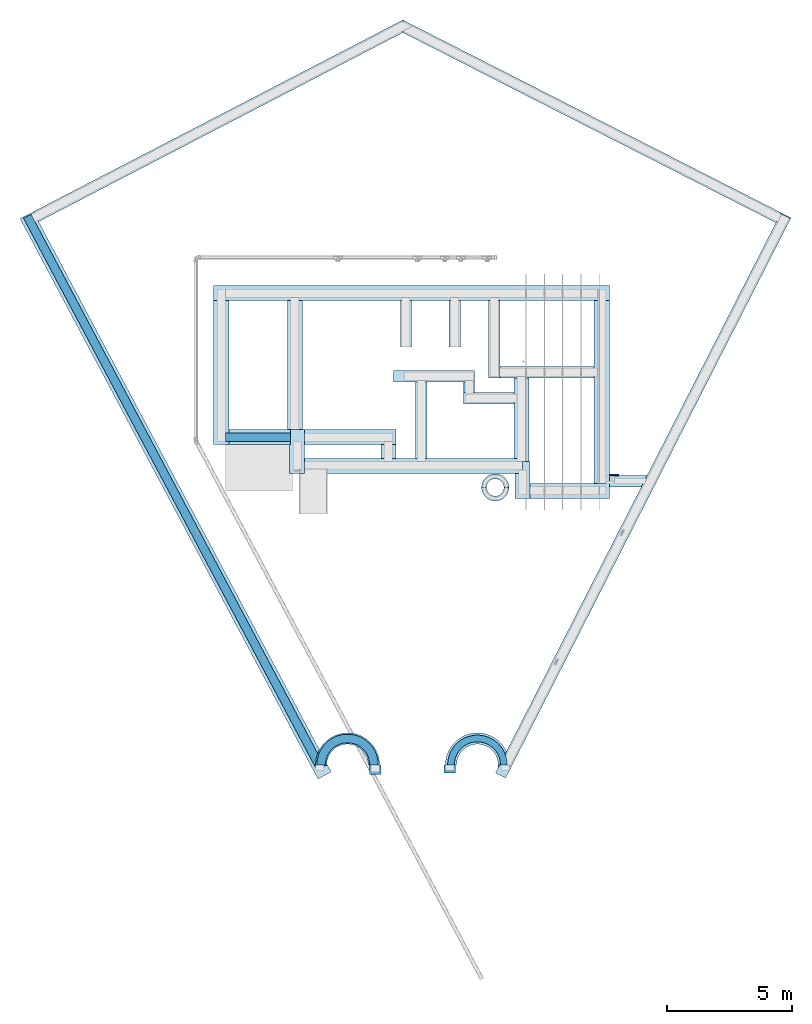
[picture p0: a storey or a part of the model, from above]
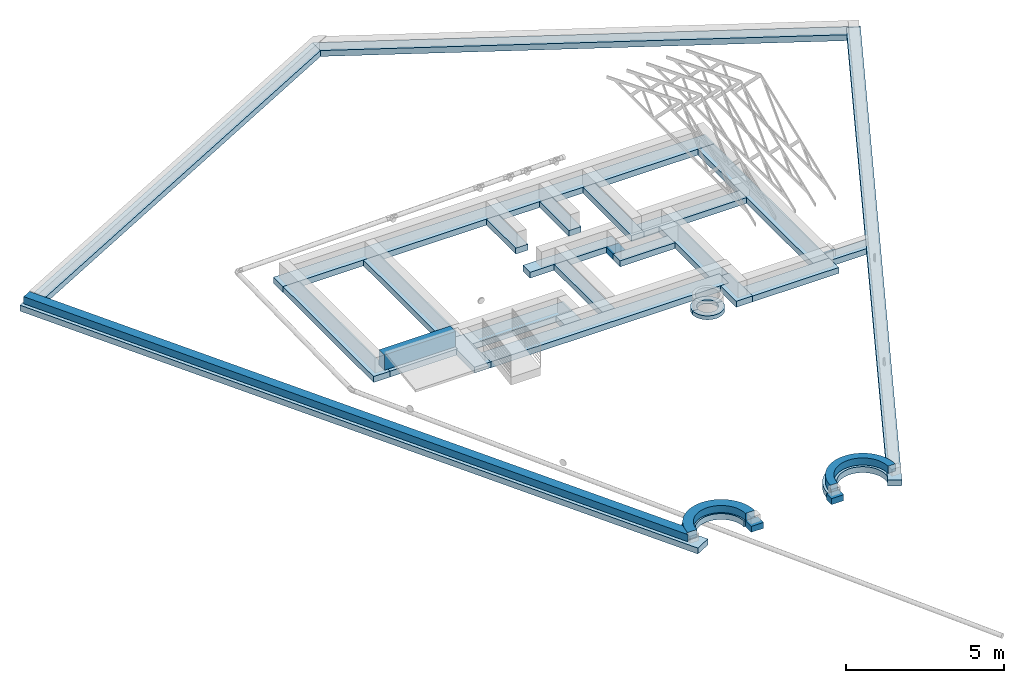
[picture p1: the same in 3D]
Properties of the parts of a building model (IFC2X3)

# File
Description: ViewDefinition [CoordinationView_V2.0]
File name: 0001
Time: 2018-05-10T18:16:20
Written by: The EXPRESS Data Manager Version 5.02.0100.07 : 28 Aug 2013
Made in: 20170223_1515(x64) - Exporter 18.0.0.420 - Alternate UI 18.0.0.420
Comment: STEP Physical File produced by: The EXPRESS Data Manager Version 5.02.0100.07 : 28 Aug 2013 * Module: EDMstepFileFactory/EDMstandAlone * Creation date: Thu May 10 18:16:20 2018 * Host: FRANCOIS-PC * Database: C:\Users\FRANCOIS\AppData\Local\Temp\{5CE646DC-1090-4634-A6B7-1711BA123ACB}\ifc * Database version: 5507 * Database creation date: Thu May 10 18:15:25 2018 * Schema: IFC2X3 * Model: DataRepository.ifc * Model creation date: Thu May 10 18:15:27 2018 * Header model: DataRepository.ifc_HeaderModel * Header model creation date: Thu May 10 18:15:27 2018 * EDMuser: sdai-user * EDMgroup: sdai-group * License ID and type: 5605 : Permanent license. Expiry date: * EDMstepFileFactory options: 020000

# IfcProject, 0001
LongName: Project Name; Phase: Project Status

# IfcSite, Surface:265088
RefLatitude: 42, 21, 31, 181945; RefLongitude: -71, -3, -24, -263305; RefElevation: 0 mm

# IfcBuilding
Pset_BuildingCommon - NumberOfStoreys: 4

# IfcBuildingStorey (4)
Name | LongName | Elevation (mm)
T.O.F | T.O.F | -445
N.G.L | N.G.L | 0
F.F.L | F.F.L | 300
U.S.W.P | U.S.W.P | 2765

# IfcSpace (23)
InteriorOrExteriorSpace: INTERNAL
Name | In | LongName | Reference | Category
1 | N.G.L | Room | Room 1 | Rooms
2 | N.G.L | Room | Room 2 | Rooms
8 | N.G.L | Porch | Porch 8 | Rooms
9 | N.G.L | Room | Room 9 | Rooms
5 | F.F.L | Bedroom 1 | Bedroom 1 5 | Rooms
9 | F.F.L | Bedroom 3 | Bedroom 3 9 | Rooms
7 | F.F.L | Bedroom 2 | Bedroom 2 7 | Rooms
3 | F.F.L | W.C1 | W.C1 3 | Rooms
4 | F.F.L | W.C2 | W.C2 4 | Rooms
1 | F.F.L | Garage | Garage 1 | Rooms
17 | F.F.L | Room | Room 17 | Rooms
6 | F.F.L | Living Room | Living Room 6 | Rooms
2 | F.F.L | Kitchen | Kitchen 2 | Rooms
2 | F.F.L | Area | Area 2 | Areas | Group: GroundFloor1
3 | F.F.L | Area | Area 3 | Areas | Group: GroundFloor1
4 | F.F.L | Area | Area 4 | Areas | Group: GroundFloor1
5 | F.F.L | Area | Area 5 | Areas | Group: GroundFloor1
6 | F.F.L | Area | Area 6 | Areas | Group: GroundFloor1
7 | F.F.L | Area | Area 7 | Areas | Group: GroundFloor1
8 | F.F.L | Area | Area 8 | Areas | Group: GroundFloor1
9 | F.F.L | Area | Area 9 | Areas | Group: GroundFloor1
10 | F.F.L | Area | Area 10 | Areas | Group: GroundFloor1
11 | F.F.L | Area | Area 11 | Areas | Group: GroundFloor1

# IfcBeam: M_Glulam-Southern Pine:Wallplate 114x38 (5)
In: F.F.L
Type - PredefinedType: BEAM
Material: Softwood, Lumber
Pset_BeamCommon - LoadBearing: yes; Reference: Wallplate 114x38; Slope: 0 deg
Name (M_Glulam-Southern Pine:Wallplate 114x38:...) | IsExternal | Span (mm)
582201 | yes | 760.545
582523 | yes | 8780
582673 | yes | 2460
582875 | yes | 15162.1
1915753 | no | 1200

# IfcBuildingElementProxy: 152 L, M_Water Heater:152 L:386241
In: F.F.L
Pset_BuildingElementProxyCommon - Reference: 152 L
Group: Domestic Cold Water 1; Domestic Hot Water 1

# IfcBuildingElementProxy: 6' Mtl Gate, Ornamental_Gate_5113:6' Mtl Gate:594094
In: F.F.L
Pset_BuildingElementProxyCommon - Reference: 6' Mtl Gate

# IfcBuildingElementProxy: Add Product code and Short description here (2)
Type - PredefinedType: USERDEFINED; Classification: C1030200 Bath & Toilet Accessories (Uniformat); Material: IS_RenderMaterial_VitreousChina
Pset_BuildingElementProxyCommon - Reference: Add Product code and Short description here
Pset_ManufacturerTypeInformation - Manufacturer: sav@idealstandard.com
Name (POR_Hercule_E3006_BIM_FR-1:Add Product code and Short description here:...) | In | Group
332737 | F.F.L | Sanitary 1
344076 | 3 | Domestic Cold Water 1; Sanitary 2

# IfcBuildingElementProxy: Australian Tree Fern - 1.8 Meters, M_RPC Tree - Tropical:Australian Tree Fern - 1.8 Meters:604156
In: 1
Pset_BuildingElementProxyCommon - Reference: Australian Tree Fern - 1.8 Meters

# IfcBuildingElementProxy: E886801 - HERCULE Reservoir Blanc SI 6/3L (2)
Type - PredefinedType: USERDEFINED; Classification: C1030200 Bath & Toilet Accessories (Uniformat); Material: IS_RenderMaterial_VitreousChina, Steel, Polished
Pset_BuildingElementProxyCommon - Reference: E886801 - HERCULE Reservoir Blanc SI 6/3L
Pset_ManufacturerTypeInformation - Manufacturer: sav@idealstandard.com
Name (POR_Hercule_E8868_BIM_FR:E886801 - HERCULE Reservoir Blanc SI 6/3L:...) | In
332739 | 4
344078 | 3

# IfcBuildingElementProxy: Fascia:Fascia (4)
In: F.F.L
Pset_BuildingElementProxyCommon - Reference: Fascia

# IfcBuildingElementProxy: Gate_15571 (1), Gate_15571 (1):Gate_15571 (1):599620
In: N.G.L
Type - Material: Steel, Galvanized
Pset_BuildingElementProxyCommon - Reference: Gate_15571 (1)

# IfcBuildingElementProxy: Generic Models 1 (3)
In: U.S.W.P
Type - Material: TIMBER
Pset_BuildingElementProxyCommon - Reference: Generic Models 1
Name
Generic Models 1:Generic Models 1:682491
Generic Models 2:Generic Models 1:682678
Generic Models 3:Generic Models 1:682852

# IfcBuildingElementProxy: Generic Models 4 (5)
In: U.S.W.P
Pset_BuildingElementProxyCommon - Reference: Generic Models 4
Name
Generic Models 4:Generic Models 4:683182
Generic Models 7:Generic Models 4:683199
Generic Models 8:Generic Models 4:683214
Generic Models 6:Generic Models 4:683230
Generic Models 5:Generic Models 4:683248

# IfcBuildingElementProxy: Generic Models 9, Generic Models 9:Generic Models 9:683304
In: U.S.W.P
Type - Material: ROOF
Pset_BuildingElementProxyCommon - Reference: Generic Models 9

# IfcBuildingElementProxy: M_RPC Beetle, M_RPC Beetle:M_RPC Beetle:750963
In: 1
Pset_BuildingElementProxyCommon - Reference: M_RPC Beetle

# IfcBuildingElementProxy: M_Refrigerator_Electrolux_DF45, M_Refrigerator_Electrolux_DF45:M_Refrigerator_Electrolux_DF45:778271
In: 2
Pset_BuildingElementProxyCommon - Reference: M_Refrigerator_Electrolux_DF45

# IfcBuildingElementProxy: P513201 - SEAT & COVER WHITE C/W METAL HINGES (2)
Type - PredefinedType: USERDEFINED; Classification: C1030200 Bath & Toilet Accessories (Uniformat); Material: Snow
Pset_BuildingElementProxyCommon - Reference: P513201 - SEAT & COVER WHITE C/W METAL HINGES
Pset_ManufacturerTypeInformation - Manufacturer: sav@idealstandard.com
Name (POR_Multisuite_P5132_BIM_FR:P513201 - SEAT & COVER WHITE C/W METAL HINGES:...) | In
332738 | 4
344077 | 3

# IfcBuildingElementProxy: STRUCTURE (12)
In: U.S.W.P
Type - Material: TIMBER 2
Pset_BuildingElementProxyCommon - Reference: STRUCTURE
Name (STRUCTURE:STRUCTURE:...)
682454
682455
682456
682457
682458
682459
682460
682461
682462
682463
682464
682473

# IfcBuildingElementProxy: STRUCTURE 2 (4)
In: U.S.W.P
Type - Material: TIMBER 2
Pset_BuildingElementProxyCommon - Reference: STRUCTURE 2
Name (STRUCTURE 2:STRUCTURE 2:...)
682453
682466
682467
682468

# IfcBuildingElementProxy: STRUCTURE 3 (5)
In: T.O.F
Type - Material: TIMBER 3
Pset_BuildingElementProxyCommon - Reference: STRUCTURE 3
Name (STRUCTURE 3:STRUCTURE 3:...)
682465
682469
682470
682471
682472

# IfcCovering: Compound Ceiling:600 x 1200mm grid (8)
In: F.F.L
PredefinedType: CEILING; Material: Default 36 mm, Gypsum Wall Board (1) 16 mm
Pset_CoveringCommon - Reference: 600 x 1200mm grid; Finish: Gypsum Wall Board (1);; TotalThickness: 52 mm
Name (Compound Ceiling:600 x 1200mm grid:...)
300172
300216
300995
301491
301730
302004
302481
528829

# IfcCovering: Roof Soffit:Generic - 300mm (2)
In: U.S.W.P
PredefinedType: CEILING; Material: Default Roof 4 mm
Pset_CoveringCommon - Reference: Generic - 300mm; TotalThickness: 4 mm
Name (Roof Soffit:Generic - 300mm:...)
842639
842657

# IfcCovering: Roof Soffit:Gypsum - 4mm (2)
In: U.S.W.P
PredefinedType: CEILING; Material: Default Roof 4 mm
Pset_CoveringCommon - Reference: Gypsum - 4mm; TotalThickness: 4 mm
Name (Roof Soffit:Gypsum - 4mm:...)
842628
842650

# IfcDistributionPort (398)
Description: Flow
Name | FlowDirection | Group
InPort_349672 | SINK | Sanitary 1
OutPort_332737 | SOURCE | Sanitary 1
2 x InPort_334164 | SOURCEANDSINK | Hydronic Supply 8
OutPort_517310 | SOURCEANDSINK | Hydronic Supply 8
2 x OutPort_334181 | SOURCEANDSINK | Hydronic Supply 8
InPort_334175 | SOURCEANDSINK | Hydronic Supply 8
InPort_334446 | SINK | Hydronic Supply 8
OutPort_367526 | SOURCE | Hydronic Supply 8
InPort_344076 | SINK | Domestic Cold Water 1
OutPort_763469 | SOURCE | Domestic Cold Water 1
InPort_363313 | SINK | Sanitary 2
OutPort_344076 | SOURCE | Sanitary 2
InPort_349611 | SINK | Hydronic Supply 8
OutPort_769102 | SOURCE | Hydronic Supply 8
InPort_349672 | SINK | Sanitary 1; Hydronic Supply 8
OutPort_349683 | SOURCE | Sanitary 1; Hydronic Supply 8
InPort_769089 | SINK | Hydronic Supply 8
OutPort_349683 | SOURCE | Hydronic Supply 8
InPort_349683 | SINK | Hydronic Supply 8
OutPort_367502 | SOURCE | Hydronic Supply 8
InPort_350644 | SINK | Domestic Cold Water 1
OutPort_351452 | SOURCE | Domestic Cold Water 1
InPort_763440 | SINK | Domestic Cold Water 1
OutPort_350644 | SOURCE | Domestic Cold Water 1
InPort_351180 | SOURCEANDSINK | Domestic Cold Water 1
2 x OutPort_351184 | SOURCEANDSINK | Domestic Cold Water 1
2 x InPort_351182 | SOURCEANDSINK | Domestic Cold Water 1
2 x OutPort_351188 | SOURCEANDSINK | Domestic Cold Water 1
2 x InPort_351186 | SOURCEANDSINK | Domestic Cold Water 1
OutPort_351192 | SOURCEANDSINK | Domestic Cold Water 1
InPort_351192 | SOURCEANDSINK | Domestic Cold Water 1
2 x OutPort_366486 | SOURCEANDSINK | Domestic Cold Water 1
InPort_351452 | SINK | Domestic Cold Water 1
OutPort_351440 | SOURCE | Domestic Cold Water 1
InPort_351440 | SINK | Domestic Cold Water 1
OutPort_351448 | SOURCE | Domestic Cold Water 1
2 x InPort_351448 | SOURCEANDSINK | Domestic Cold Water 1
2 x OutPort_366517 | SOURCEANDSINK | Domestic Cold Water 1
2 x OutPort_463083 | SOURCEANDSINK | Domestic Cold Water 1
InPort_358016 | SINK | Hydronic Supply 2
OutPort_356694 | SOURCE | Hydronic Supply 2
InPort_356694 | SINK | Domestic Hot Water 1
OutPort_408237 | SOURCE | Domestic Hot Water 1
InPort_356694 | SINK | Domestic Cold Water 1
OutPort_357895 | SOURCE | Domestic Cold Water 1
InPort_357895 | SINK | Domestic Cold Water 1
OutPort_357973 | SOURCE | Domestic Cold Water 1
InPort_357963 | SINK | Domestic Cold Water 1
OutPort_357977 | SOURCE | Domestic Cold Water 1
InPort_357973 | SINK | Domestic Cold Water 1
OutPort_357963 | SOURCE | Domestic Cold Water 1
2 x InPort_357977 | SOURCEANDSINK | Domestic Cold Water 1
OutPort_366509 | SOURCEANDSINK | Domestic Cold Water 1
OutPort_527207 | SOURCEANDSINK | Domestic Cold Water 1
InPort_362038 | SOURCEANDSINK | Hydronic Supply 4
OutPort_363255 | SOURCEANDSINK | Hydronic Supply 4
InPort_363276 | SOURCEANDSINK | Hydronic Supply 8
OutPort_368122 | SOURCEANDSINK | Hydronic Supply 8
InPort_363313 | SINK | Hydronic Supply 8; Sanitary 2
OutPort_363329 | SOURCE | Hydronic Supply 8; Sanitary 2
2 x InPort_363329 | SOURCEANDSINK | Hydronic Supply 8
2 x OutPort_764122 | SOURCEANDSINK | Hydronic Supply 8
OutPort_367613 | SOURCEANDSINK | Hydronic Supply 8
InPort_366079 | SINK | Domestic Cold Water 1
OutPort_366500 | SOURCE | Domestic Cold Water 1
InPort_366079 | SINK | Domestic Hot Water 1
OutPort_761551 | SOURCE | Domestic Hot Water 1
InPort_366115 | SINK | Domestic Hot Water 1
OutPort_514019 | SOURCE | Domestic Hot Water 1
InPort_366115 | SINK | Domestic Cold Water 1
OutPort_366465 | SOURCE | Domestic Cold Water 1
2 x InPort_366954 | SINK | Sanitary 6
OutPort_366115 | SOURCE | Sanitary 6
InPort_366465 | SINK | Domestic Cold Water 1
OutPort_366481 | SOURCE | Domestic Cold Water 1
InPort_366481 | SINK | Domestic Cold Water 1
OutPort_366467 | SOURCE | Domestic Cold Water 1
InPort_366467 | SINK | Domestic Cold Water 1
OutPort_366485 | SOURCE | Domestic Cold Water 1
2 x InPort_366476 | SOURCEANDSINK | Domestic Cold Water 1
OutPort_366485 | SOURCEANDSINK | Domestic Cold Water 1
2 x OutPort_463082 | SOURCEANDSINK | Domestic Cold Water 1
InPort_366485 | SOURCEANDSINK | Domestic Cold Water 1
InPort_366500 | SINK | Domestic Cold Water 1
OutPort_366512 | SOURCE | Domestic Cold Water 1
InPort_366502 | SINK | Domestic Cold Water 1
OutPort_366516 | SOURCE | Domestic Cold Water 1
InPort_366512 | SINK | Domestic Cold Water 1
OutPort_366502 | SOURCE | Domestic Cold Water 1
InPort_366509 | SOURCEANDSINK | Domestic Cold Water 1
OutPort_366516 | SOURCEANDSINK | Domestic Cold Water 1
InPort_366516 | SOURCEANDSINK | Domestic Cold Water 1
InPort_366810 | SINK | Hydronic Supply 8; Sanitary 7
OutPort_367240 | SOURCE | Hydronic Supply 8; Sanitary 7
InPort_366115 | SINK | Sanitary 6
OutPort_366954 | SOURCE | Sanitary 6
OutPort_366962 | SOURCE | Sanitary 6
InPort_366962 | SINK | Sanitary 6
OutPort_385773 | SOURCE | Sanitary 6
InPort_367240 | SINK | Hydronic Supply 8
OutPort_764119 | SOURCE | Hydronic Supply 8
InPort_367502 | SINK | Hydronic Supply 8
OutPort_367523 | SOURCE | Hydronic Supply 8
InPort_367504 | SINK | Hydronic Supply 8
OutPort_367533 | SOURCE | Hydronic Supply 8
InPort_367523 | SINK | Hydronic Supply 8
OutPort_367504 | SOURCE | Hydronic Supply 8
InPort_367525 | SINK | Hydronic Supply 8
OutPort_764747 | SOURCE | Hydronic Supply 8
InPort_367526 | SINK | Hydronic Supply 8
2 x OutPort_367525 | SOURCE | Hydronic Supply 8
InPort_367533 | SINK | Hydronic Supply 8
InPort_367613 | SOURCEANDSINK | Hydronic Supply 8
2 x OutPort_367629 | SOURCEANDSINK | Hydronic Supply 8
2 x InPort_367615 | SOURCEANDSINK | Hydronic Supply 8
2 x OutPort_367639 | SOURCEANDSINK | Hydronic Supply 8
3 x InPort_367631 | SOURCEANDSINK | Hydronic Supply 8
2 x OutPort_1316433 | SOURCEANDSINK | Hydronic Supply 8
2 x OutPort_368151 | SOURCEANDSINK | Hydronic Supply 8
InPort_368122 | SOURCEANDSINK | Hydronic Supply 8
2 x OutPort_368146 | SOURCEANDSINK | Hydronic Supply 8
2 x InPort_368127 | SOURCEANDSINK | Hydronic Supply 8
2 x OutPort_368158 | SOURCEANDSINK | Hydronic Supply 8
3 x InPort_368150 | SOURCEANDSINK | Hydronic Supply 8
2 x OutPort_517352 | SOURCEANDSINK | Hydronic Supply 8
InPort_385773 | SINK | Sanitary 6
OutPort_769099 | SOURCE | Sanitary 6
InPort_409378 | SINK | Domestic Hot Water 1
OutPort_386241 | SOURCE | Domestic Hot Water 1
InPort_386241 | SINK | Domestic Cold Water 1
OutPort_405806 | SOURCE | Domestic Cold Water 1
InPort_391891 | SOURCEANDSINK | Hydronic Supply 6
OutPort_528896 | SOURCEANDSINK | Hydronic Supply 6
InPort_405806 | SINK | Domestic Cold Water 1
OutPort_527250 | SOURCE | Domestic Cold Water 1
InPort_527291 | SINK | Domestic Cold Water 1
OutPort_405808 | SOURCE | Domestic Cold Water 1
InPort_405808 | SINK | Domestic Cold Water 1
OutPort_527206 | SOURCE | Domestic Cold Water 1
2 x InPort_405838 | SOURCEANDSINK | Domestic Cold Water 1
2 x OutPort_527210 | SOURCEANDSINK | Domestic Cold Water 1
2 x OutPort_513136 | SOURCEANDSINK | Domestic Cold Water 1
InPort_408237 | SINK | Domestic Hot Water 1
OutPort_408253 | SOURCE | Domestic Hot Water 1
InPort_408241 | SINK | Domestic Hot Water 1
OutPort_408243 | SOURCE | Domestic Hot Water 1
InPort_408253 | SINK | Domestic Hot Water 1
OutPort_408241 | SOURCE | Domestic Hot Water 1
2 x InPort_408243 | SOURCEANDSINK | Domestic Hot Water 1
OutPort_527109 | SOURCEANDSINK | Domestic Hot Water 1
2 x OutPort_514055 | SOURCEANDSINK | Domestic Hot Water 1
2 x InPort_408244 | SOURCEANDSINK | Domestic Hot Water 1
2 x OutPort_463129 | SOURCEANDSINK | Domestic Hot Water 1
2 x OutPort_514054 | SOURCEANDSINK | Domestic Hot Water 1
InPort_526302 | SINK | Domestic Hot Water 1
OutPort_409378 | SOURCE | Domestic Hot Water 1
InPort_436318 | SOURCEANDSINK | Domestic Cold Water 1
OutPort_472611 | SOURCEANDSINK | Domestic Cold Water 1
InPort_436318 | SOURCEANDSINK | Domestic Hot Water 1
OutPort_463758 | SOURCEANDSINK | Domestic Hot Water 1
2 x InPort_463074 | SOURCEANDSINK | Domestic Cold Water 1
2 x OutPort_472617 | SOURCEANDSINK | Domestic Cold Water 1
2 x OutPort_463092 | SOURCEANDSINK | Domestic Cold Water 1
2 x InPort_463080 | SOURCEANDSINK | Domestic Cold Water 1
InPort_463082 | SOURCEANDSINK | Domestic Cold Water 1
2 x InPort_463121 | SOURCEANDSINK | Domestic Hot Water 1
2 x OutPort_463139 | SOURCEANDSINK | Domestic Hot Water 1
2 x OutPort_463764 | SOURCEANDSINK | Domestic Hot Water 1
2 x InPort_463127 | SOURCEANDSINK | Domestic Hot Water 1
InPort_463130 | SINK | Domestic Hot Water 1
OutPort_463129 | SOURCE | Domestic Hot Water 1
InPort_514025 | SINK | Domestic Hot Water 1
OutPort_463130 | SOURCE | Domestic Hot Water 1
InPort_463758 | SOURCEANDSINK | Domestic Hot Water 1
2 x OutPort_463772 | SOURCEANDSINK | Domestic Hot Water 1
2 x InPort_463762 | SOURCEANDSINK | Domestic Hot Water 1
InPort_472611 | SOURCEANDSINK | Domestic Cold Water 1
2 x OutPort_472625 | SOURCEANDSINK | Domestic Cold Water 1
2 x InPort_472615 | SOURCEANDSINK | Domestic Cold Water 1
2 x InPort_515041 | SINK | Sanitary 4
2 x OutPort_511864 | SOURCE | Sanitary 4
InPort_515243 | SINK | Sanitary 4
InPort_511864 | SINK | Domestic Hot Water 1
OutPort_761439 | SOURCE | Domestic Hot Water 1
InPort_511864 | SINK | Domestic Cold Water 1
OutPort_513116 | SOURCE | Domestic Cold Water 1
InPort_513116 | SINK | Domestic Cold Water 1
OutPort_513132 | SOURCE | Domestic Cold Water 1
InPort_513120 | SINK | Domestic Cold Water 1
OutPort_513136 | SOURCE | Domestic Cold Water 1
InPort_513132 | SINK | Domestic Cold Water 1
OutPort_513120 | SOURCE | Domestic Cold Water 1
2 x InPort_513127 | SOURCEANDSINK | Domestic Cold Water 1
OutPort_517527 | SOURCEANDSINK | Domestic Cold Water 1
InPort_513627 | SINK | Domestic Hot Water 1
OutPort_527112 | SOURCE | Domestic Hot Water 1
InPort_514599 | SINK | Domestic Hot Water 1
OutPort_513627 | SOURCE | Domestic Hot Water 1
InPort_514019 | SINK | Domestic Hot Water 1
OutPort_514033 | SOURCE | Domestic Hot Water 1
InPort_514023 | SINK | Domestic Hot Water 1
OutPort_514025 | SOURCE | Domestic Hot Water 1
InPort_514033 | SINK | Domestic Hot Water 1
OutPort_514023 | SOURCE | Domestic Hot Water 1
2 x InPort_514052 | SOURCEANDSINK | Domestic Hot Water 1
OutPort_761523 | SOURCEANDSINK | Domestic Hot Water 1
InPort_514054 | SOURCEANDSINK | Domestic Hot Water 1
InPort_761453 | SINK | Domestic Hot Water 1
OutPort_514591 | SOURCE | Domestic Hot Water 1
InPort_514591 | SINK | Domestic Hot Water 1
OutPort_514599 | SOURCE | Domestic Hot Water 1
OutPort_516011 | SOURCE | Sanitary 4
InPort_511864 | SINK | Sanitary 4
OutPort_515041 | SOURCE | Sanitary 4
InPort_515762 | SINK | Sanitary 4
OutPort_515243 | SOURCE | Sanitary 4
InPort_516499 | SINK | Sanitary 4
OutPort_515762 | SOURCE | Sanitary 4
InPort_516011 | SINK | Sanitary 4
OutPort_516522 | SOURCE | Sanitary 4
2 x InPort_516521 | SINK | Sanitary 4
OutPort_516499 | SOURCE | Sanitary 4
OutPort_516502 | SOURCE | Sanitary 4
InPort_516502 | SINK | Sanitary 4
OutPort_516773 | SOURCE | Sanitary 4
InPort_516522 | SINK | Sanitary 4
OutPort_516521 | SOURCE | Sanitary 4
InPort_516773 | SINK | Hydronic Supply 8; Sanitary 4
OutPort_517329 | SOURCE | Hydronic Supply 8; Sanitary 4
InPort_517310 | SOURCEANDSINK | Hydronic Supply 8
OutPort_517338 | SOURCEANDSINK | Hydronic Supply 8
InPort_517329 | SINK | Hydronic Supply 8
OutPort_517347 | SOURCE | Hydronic Supply 8
InPort_517331 | SINK | Hydronic Supply 8
OutPort_517359 | SOURCE | Hydronic Supply 8
InPort_517347 | SINK | Hydronic Supply 8
OutPort_517331 | SOURCE | Hydronic Supply 8
InPort_517338 | SOURCEANDSINK | Hydronic Supply 8
OutPort_517351 | SOURCEANDSINK | Hydronic Supply 8
InPort_517359 | SINK | Hydronic Supply 8
OutPort_517351 | SOURCE | Hydronic Supply 8
InPort_517351 | SOURCEANDSINK | Hydronic Supply 8
InPort_517527 | SOURCEANDSINK | Domestic Cold Water 1
OutPort_517539 | SOURCEANDSINK | Domestic Cold Water 1
InPort_517539 | SOURCEANDSINK | Domestic Cold Water 1
2 x OutPort_517560 | SOURCEANDSINK | Domestic Cold Water 1
2 x InPort_517548 | SOURCEANDSINK | Domestic Cold Water 1
2 x OutPort_517575 | SOURCEANDSINK | Domestic Cold Water 1
2 x InPort_517564 | SOURCEANDSINK | Domestic Cold Water 1
2 x OutPort_517594 | SOURCEANDSINK | Domestic Cold Water 1
InPort_517577 | SOURCEANDSINK | Domestic Cold Water 1
InPort_527371 | SINK | Domestic Hot Water 1
OutPort_526302 | SOURCE | Domestic Hot Water 1
InPort_526766 | SINK | Domestic Hot Water 1
OutPort_527383 | SOURCE | Domestic Hot Water 1
InPort_526980 | SINK | Domestic Hot Water 1
OutPort_526766 | SOURCE | Domestic Hot Water 1
InPort_526978 | SINK | Domestic Hot Water 1
OutPort_526980 | SOURCE | Domestic Hot Water 1
InPort_527177 | SINK | Domestic Hot Water 1
OutPort_526978 | SOURCE | Domestic Hot Water 1
InPort_527025 | SINK | Domestic Hot Water 1
OutPort_527181 | SOURCE | Domestic Hot Water 1
InPort_527108 | SINK | Domestic Hot Water 1
OutPort_527025 | SOURCE | Domestic Hot Water 1
InPort_527108 | SOURCEANDSINK | Domestic Hot Water 1
2 x OutPort_527114 | SOURCEANDSINK | Domestic Hot Water 1
InPort_527112 | SINK | Domestic Hot Water 1
OutPort_527108 | SOURCE | Domestic Hot Water 1
InPort_527109 | SOURCEANDSINK | Domestic Hot Water 1
InPort_527181 | SINK | Domestic Hot Water 1
OutPort_527168 | SOURCE | Domestic Hot Water 1
InPort_527168 | SINK | Domestic Hot Water 1
OutPort_527177 | SOURCE | Domestic Hot Water 1
2 x InPort_527206 | SOURCEANDSINK | Domestic Cold Water 1
2 x OutPort_527212 | SOURCEANDSINK | Domestic Cold Water 1
InPort_527207 | SOURCEANDSINK | Domestic Cold Water 1
InPort_527250 | SINK | Domestic Cold Water 1
OutPort_527248 | SOURCE | Domestic Cold Water 1
InPort_527248 | SINK | Domestic Cold Water 1
OutPort_527287 | SOURCE | Domestic Cold Water 1
InPort_527281 | SINK | Domestic Cold Water 1
OutPort_527291 | SOURCE | Domestic Cold Water 1
InPort_527287 | SINK | Domestic Cold Water 1
OutPort_527281 | SOURCE | Domestic Cold Water 1
InPort_527381 | SINK | Domestic Hot Water 1
OutPort_527371 | SOURCE | Domestic Hot Water 1
InPort_527373 | SINK | Domestic Hot Water 1
OutPort_527381 | SOURCE | Domestic Hot Water 1
InPort_527383 | SINK | Domestic Hot Water 1
OutPort_527373 | SOURCE | Domestic Hot Water 1
InPort_761439 | SINK | Domestic Hot Water 1
OutPort_761449 | SOURCE | Domestic Hot Water 1
InPort_761441 | SINK | Domestic Hot Water 1
OutPort_761453 | SOURCE | Domestic Hot Water 1
InPort_761449 | SINK | Domestic Hot Water 1
OutPort_761441 | SOURCE | Domestic Hot Water 1
InPort_763469 | SINK | Domestic Cold Water 1
OutPort_763440 | SOURCE | Domestic Cold Water 1
InPort_763900 | SINK | Hydronic Supply 8
OutPort_764130 | SOURCE | Hydronic Supply 8
InPort_764119 | SINK | Hydronic Supply 8
OutPort_763900 | SOURCE | Hydronic Supply 8
InPort_764034 | SOURCEANDSINK | Hydronic Supply 8
OutPort_764121 | SOURCEANDSINK | Hydronic Supply 8
InPort_764130 | SINK | Hydronic Supply 8
OutPort_764121 | SOURCE | Hydronic Supply 8
InPort_764121 | SOURCEANDSINK | Hydronic Supply 8
InPort_764593 | SOURCEANDSINK | Hydronic Supply 8
OutPort_764737 | SOURCEANDSINK | Hydronic Supply 8
InPort_764737 | SOURCEANDSINK | Hydronic Supply 8
OutPort_1316241 | SOURCEANDSINK | Hydronic Supply 8
InPort_764747 | SINK | Hydronic Supply 8
OutPort_1316432 | SOURCE | Hydronic Supply 8
InPort_769099 | SINK | Hydronic Supply 8; Sanitary 6
OutPort_769086 | SOURCE | Hydronic Supply 8; Sanitary 6
InPort_769086 | SINK | Hydronic Supply 8
OutPort_769109 | SOURCE | Hydronic Supply 8
InPort_769101 | SINK | Hydronic Supply 8
OutPort_769089 | SOURCE | Hydronic Supply 8
InPort_769102 | SINK | Hydronic Supply 8
2 x OutPort_769101 | SOURCE | Hydronic Supply 8
InPort_769109 | SINK | Hydronic Supply 8
InPort_1316241 | SOURCEANDSINK | Hydronic Supply 8
OutPort_1316409 | SOURCEANDSINK | Hydronic Supply 8
InPort_1316409 | SOURCEANDSINK | Hydronic Supply 8
2 x OutPort_1316428 | SOURCEANDSINK | Hydronic Supply 8
2 x InPort_1316411 | SOURCEANDSINK | Hydronic Supply 8
2 x OutPort_1316440 | SOURCEANDSINK | Hydronic Supply 8
2 x InPort_1316432 | SOURCEANDSINK | Hydronic Supply 8

# IfcDoor: 0813 x 2134mm (2)
In: F.F.L
Type - OperationType: SINGLE_SWING_RIGHT; ParameterTakesPrecedence: no; Sizeable: no; Material: Door - Frame, Door - Panel
Type - M_Single-Flush:0813 x 2134mm:282405 - PanelOperation: SWINGING
OverallHeight: 2134 mm; OverallWidth: 813 mm
Pset_DoorCommon - IsExternal: no; Reference: 0813 x 2134mm
Pset_ManufacturerTypeInformation - Manufacturer: Swartland
Name (M_Single-Flush:0813 x 2134mm:...)
282405
282503

# IfcDoor: 0813 x 2134mm, M_Single-Flush:0813 x 2134mm:842625
In: F.F.L
Type - OperationType: SINGLE_SWING_RIGHT; ParameterTakesPrecedence: no; Sizeable: no; Material: Door - Frame, Door - Panel
Type - M_Single-Flush:0813 x 2134mm:842625 - PanelOperation: SWINGING
OverallHeight: 2134 mm; OverallWidth: 813 mm
Pset_DoorCommon - IsExternal: no; Reference: 0813 x 2134mm
Pset_ManufacturerTypeInformation - Manufacturer: Swartland

# IfcDoor: 0813 x 2134mm, M_Single-Glass 2:0813 x 2134mm:373462
In: F.F.L
Type - OperationType: SINGLE_SWING_RIGHT; ParameterTakesPrecedence: no; Sizeable: no; Material: Meranti - Varnish Mat, Glass
Type - M_Single-Glass 2:0813 x 2134mm:373462 - PanelOperation: SWINGING
OverallHeight: 2134 mm; OverallWidth: 813 mm
Pset_DoorCommon - IsExternal: no; Reference: 0813 x 2134mm; ThermalTransmittance: 3.6886 kg/K/s3
Pset_ManufacturerTypeInformation - Manufacturer: Swartland

# IfcDoor: 0915 x 2134mm, M_Single-Flush:0915 x 2134mm:283172
In: F.F.L
Type - OperationType: SINGLE_SWING_LEFT; ParameterTakesPrecedence: no; Sizeable: no; Material: Door - Frame, Door - Panel
Type - M_Single-Flush:0915 x 2134mm:283172 - PanelOperation: SWINGING
OverallHeight: 2134 mm; OverallWidth: 915 mm
Pset_DoorCommon - IsExternal: no; Reference: 0915 x 2134mm
Pset_ManufacturerTypeInformation - Manufacturer: Swartland

# IfcDoor: 0915 x 2134mm, M_Single-Flush:0915 x 2134mm:283297
In: F.F.L
Type - OperationType: SINGLE_SWING_LEFT; ParameterTakesPrecedence: no; Sizeable: no; Material: Door - Frame, Door - Panel
Type - M_Single-Flush:0915 x 2134mm:283297 - PanelOperation: SWINGING
OverallHeight: 2134 mm; OverallWidth: 915 mm
Pset_DoorCommon - IsExternal: no; Reference: 0915 x 2134mm
Pset_ManufacturerTypeInformation - Manufacturer: Swartland

# IfcDoor: 1800 x 2100mm, M_Door-Interior-Double-Full Glass-Wood:1800 x 2100mm:291945
In: F.F.L
Type - ParameterTakesPrecedence: no; Sizeable: no; Classification: C1020120 Interior Doors - Wood (Uniformat); Material: Aluminum, Meranti - Varnish Mat, Glass
OverallHeight: 2125 mm; OverallWidth: 1850 mm
Pset_DoorCommon - IsExternal: no; Reference: 1800 x 2100mm
Pset_ManufacturerTypeInformation - Manufacturer: swartland

# IfcDoor: 2435 x 1981mm, M_Overhead-Sectional:2435 x 1981mm:306219
In: F.F.L
Type - ParameterTakesPrecedence: no; Sizeable: no; Material: Meranti - Varnish Mat
OverallHeight: 1981 mm; OverallWidth: 2435 mm
Pset_DoorCommon - IsExternal: yes; Reference: 2435 x 1981mm; ThermalTransmittance: 2.5572 kg/K/s3
Pset_ManufacturerTypeInformation - Manufacturer: Swartland

# IfcFlowFitting: Standard (90)
Pset_DistributionFlowElementCommon - Reference: Standard
Name | In | Group
M_Elbow - PVC - Sch 40:Standard:334181 | T.O.F | Hydronic Supply 8
M_Cap - PVC - Sch 40:Standard:334446 | T.O.F | Hydronic Supply 8
M_Cap - PVC - Sch 40:Standard:349611 | F.F.L | Hydronic Supply 8
M_Cap - PVC - Sch 40:Standard:349634 | F.F.L
M_Tee - PVC - Sch 40:Standard:349683 | F.F.L | Sanitary 1; Hydronic Supply 8
M_Elbow - PVC - Sch 40:Standard:351184 | 4 | Domestic Cold Water 1
M_Elbow - PVC - Sch 40:Standard:351188 | F.F.L | Domestic Cold Water 1
M_Elbow - PVC - Sch 40:Standard:351192 | F.F.L | Domestic Cold Water 1
M_Tee - PVC - Sch 40:Standard:351448 | F.F.L | Domestic Cold Water 1
M_Elbow - PVC - Sch 40:Standard:351452 | F.F.L | Domestic Cold Water 1
M_Elbow - PVC - Sch 40:Standard:357973 | F.F.L | Domestic Cold Water 1
M_Tee - PVC - Sch 40:Standard:357977 | F.F.L | Domestic Cold Water 1
M_Trap P - PVC - Sch 40 - DWV:Standard:362038 | 3 | Hydronic Supply 4
M_Elbow - PVC - Sch 40:Standard:363276 | F.F.L | Hydronic Supply 8
M_Tee - PVC - Sch 40:Standard:363329 | F.F.L | Hydronic Supply 8; Sanitary 2
M_Elbow - PVC - Sch 40:Standard:366481 | F.F.L | Domestic Cold Water 1
M_Tee - PVC - Sch 40:Standard:366485 | F.F.L | Domestic Cold Water 1
M_Elbow - PVC - Sch 40:Standard:366512 | F.F.L | Domestic Cold Water 1
M_Tee - PVC - Sch 40:Standard:366516 | F.F.L | Domestic Cold Water 1
M_Trap P - PVC - Sch 40 - DWV:Standard:366810 | 3 | Hydronic Supply 8; Sanitary 7
M_Trap P - PVC - Sch 40 - DWV:Standard:366962 | 4 | Sanitary 6
M_Elbow - PVC - Sch 40:Standard:367523 | F.F.L | Hydronic Supply 8
M_Tee - PVC - Sch 40:Standard:367525 | T.O.F | Hydronic Supply 8
M_Coupling Reducing - PVC - Sch 40:Standard:367533 | F.F.L | Hydronic Supply 8
M_Elbow - PVC - Sch 40:Standard:367629 | F.F.L | Hydronic Supply 8
M_Tee - PVC - Sch 40:Standard:367631 | T.O.F | Hydronic Supply 8
M_Coupling Reducing - PVC - Sch 40:Standard:367639 | F.F.L | Hydronic Supply 8
M_Elbow - PVC - Sch 40:Standard:368146 | F.F.L | Hydronic Supply 8
M_Tee - PVC - Sch 40:Standard:368150 | T.O.F | Hydronic Supply 8
M_Coupling Reducing - PVC - Sch 40:Standard:368158 | F.F.L | Hydronic Supply 8
M_Tee - PVC - Sch 40:Standard:408243 | F.F.L | Domestic Hot Water 1
M_Elbow - PVC - Sch 40:Standard:408253 | F.F.L | Domestic Hot Water 1
M_Tee - PVC - Sch 40:Standard:463082 | F.F.L | Domestic Cold Water 1
M_Elbow - PVC - Sch 40:Standard:463092 | F.F.L | Domestic Cold Water 1
M_Tee - PVC - Sch 40:Standard:463129 | F.F.L | Domestic Hot Water 1
M_Elbow - PVC - Sch 40:Standard:463139 | F.F.L | Domestic Hot Water 1
M_Elbow - PVC - Sch 40:Standard:463764 | F.F.L | Domestic Hot Water 1
M_Elbow - PVC - Sch 40:Standard:463772 | F.F.L | Domestic Hot Water 1
M_Elbow - PVC - Sch 40:Standard:472617 | F.F.L | Domestic Cold Water 1
M_Elbow - PVC - Sch 40:Standard:472625 | F.F.L | Domestic Cold Water 1
M_Coupling Reducing - PVC - Sch 40:Standard:506603 | F.F.L
M_Elbow - PVC - Sch 40:Standard:513132 | 2 | Domestic Cold Water 1
M_Tee - PVC - Sch 40:Standard:513136 | F.F.L | Domestic Cold Water 1
M_Elbow - PVC - Sch 40:Standard:514025 | F.F.L | Domestic Hot Water 1
M_Elbow - PVC - Sch 40:Standard:514033 | F.F.L | Domestic Hot Water 1
M_Tee - PVC - Sch 40:Standard:514054 | F.F.L | Domestic Hot Water 1
M_Elbow - PVC - Sch 40:Standard:514599 | F.F.L | Domestic Hot Water 1
M_Trap P - PVC - Sch 40 - DWV:Standard:515762 | 2 | Sanitary 4
M_Trap P - PVC - Sch 40 - DWV:Standard:516011 | 2 | Sanitary 4
M_Tee - PVC - Sch 40:Standard:516521 | 2 | Sanitary 4
M_Elbow - PVC - Sch 40:Standard:516773 | F.F.L | Hydronic Supply 8; Sanitary 4
M_Elbow - PVC - Sch 40:Standard:517310 | T.O.F | Hydronic Supply 8
M_Elbow - PVC - Sch 40:Standard:517347 | F.F.L | Hydronic Supply 8
M_Tee - PVC - Sch 40:Standard:517351 | T.O.F | Hydronic Supply 8
M_Coupling Reducing - PVC - Sch 40:Standard:517359 | F.F.L | Hydronic Supply 8
M_Elbow - PVC - Sch 40:Standard:517527 | F.F.L | Domestic Cold Water 1
M_Elbow - PVC - Sch 40:Standard:517560 | F.F.L | Domestic Cold Water 1
M_Elbow - PVC - Sch 40:Standard:517575 | F.F.L | Domestic Cold Water 1
M_Elbow - PVC - Sch 40:Standard:517594 | F.F.L | Domestic Cold Water 1
M_Elbow - PVC - Sch 40:Standard:526302 | F.F.L | Domestic Hot Water 1
M_Elbow - PVC - Sch 40:Standard:526980 | F.F.L | Domestic Hot Water 1
M_Tee - PVC - Sch 40:Standard:527108 | F.F.L | Domestic Hot Water 1
M_Coupling Reducing - PVC - Sch 40:Standard:527112 | F.F.L | Domestic Hot Water 1
M_Coupling Reducing - PVC - Sch 40:Standard:527114 | F.F.L | Domestic Hot Water 1
M_Elbow - PVC - Sch 40:Standard:527177 | 3 | Domestic Hot Water 1
M_Elbow - PVC - Sch 40:Standard:527181 | F.F.L | Domestic Hot Water 1
M_Tee - PVC - Sch 40:Standard:527206 | F.F.L | Domestic Cold Water 1
M_Coupling Reducing - PVC - Sch 40:Standard:527210 | F.F.L | Domestic Cold Water 1
M_Coupling Reducing - PVC - Sch 40:Standard:527212 | F.F.L | Domestic Cold Water 1
M_Elbow - PVC - Sch 40:Standard:527250 | F.F.L | Domestic Cold Water 1
M_Elbow - PVC - Sch 40:Standard:527287 | 3 | Domestic Cold Water 1
M_Elbow - PVC - Sch 40:Standard:527291 | F.F.L | Domestic Cold Water 1
M_Elbow - PVC - Sch 40:Standard:527381 | F.F.L | Domestic Hot Water 1
M_Elbow - PVC - Sch 40:Standard:527383 | F.F.L | Domestic Hot Water 1
M_Cross - PVC - Sch 40:Standard:682450 | T.O.F
M_Elbow - PVC - Sch 40:Standard:761449 | 2 | Domestic Hot Water 1
M_Elbow - PVC - Sch 40:Standard:761453 | F.F.L | Domestic Hot Water 1
M_Elbow - PVC - Sch 40:Standard:761523 | F.F.L | Domestic Hot Water 1
M_Elbow - PVC - Sch 40:Standard:763440 | 3 | Domestic Cold Water 1
M_Elbow - PVC - Sch 40:Standard:764119 | F.F.L | Hydronic Supply 8
M_Tee - PVC - Sch 40:Standard:764121 | F.F.L | Hydronic Supply 8
M_Coupling Reducing - PVC - Sch 40:Standard:764130 | F.F.L | Hydronic Supply 8
M_Trap P - PVC - Sch 40 - DWV:Standard:764593 | F.F.L | Hydronic Supply 8
M_Elbow - PVC - Sch 40:Standard:769099 | F.F.L | Hydronic Supply 8; Sanitary 6
M_Tee - PVC - Sch 40:Standard:769101 | F.F.L | Hydronic Supply 8
M_Coupling Reducing - PVC - Sch 40:Standard:769109 | F.F.L | Hydronic Supply 8
M_Elbow - PVC - Sch 40:Standard:1316241 | F.F.L | Hydronic Supply 8
M_Elbow - PVC - Sch 40:Standard:1316428 | F.F.L | Hydronic Supply 8
M_Tee - PVC - Sch 40:Standard:1316432 | T.O.F | Hydronic Supply 8
M_Coupling Reducing - PVC - Sch 40:Standard:1316440 | F.F.L | Hydronic Supply 8

# IfcFlowSegment: Flex Pipe Round:Flex - Round, Flex Pipe Round:Flex - Round:528896
In: F.F.L
Type - PredefinedType: FLEXIBLESEGMENT
Pset_DistributionFlowElementCommon - Reference: Flex - Round
Group: Hydronic Supply 6

# IfcFlowSegment: Gutter:Gutter:41283 (4)
Type - ElementType: Gutter:Gutter:41283; PredefinedType: GUTTER
Pset_DistributionFlowElementCommon - Reference: Gutter
Name (Gutter:Gutter:...) | In
730610 | F.F.L
730624 | F.F.L
730634 | U.S.W.P
730644 | F.F.L

# IfcFlowSegment: Pipe Types:PVC80 (98)
Pset_DistributionFlowElementCommon - Reference: PVC80
Name (Pipe Types:PVC80:...) | In | Group
334164 | T.O.F | Hydronic Supply 8
334175 | T.O.F | Hydronic Supply 8
349672 | F.F.L | Sanitary 1; Hydronic Supply 8
350644 | F.F.L | Domestic Cold Water 1
351180 | F.F.L | Domestic Cold Water 1
351182 | F.F.L | Domestic Cold Water 1
351186 | F.F.L | Domestic Cold Water 1
351440 | F.F.L | Domestic Cold Water 1
357895 | F.F.L | Domestic Cold Water 1
357963 | F.F.L | Domestic Cold Water 1
358016 | F.F.L | Hydronic Supply 2
363255 | F.F.L | Hydronic Supply 4
363313 | F.F.L | Hydronic Supply 8; Sanitary 2
366465 | F.F.L | Domestic Cold Water 1
366467 | F.F.L | Domestic Cold Water 1
366476 | F.F.L | Domestic Cold Water 1
366486 | F.F.L | Domestic Cold Water 1
366500 | F.F.L | Domestic Cold Water 1
366502 | F.F.L | Domestic Cold Water 1
366509 | F.F.L | Domestic Cold Water 1
366517 | F.F.L | Domestic Cold Water 1
366715 | F.F.L
366954 | F.F.L | Sanitary 6
367240 | F.F.L | Hydronic Supply 8; Sanitary 7
367502 | F.F.L | Hydronic Supply 8
367504 | F.F.L | Hydronic Supply 8
367526 | T.O.F | Hydronic Supply 8
367613 | F.F.L | Hydronic Supply 8
367615 | F.F.L | Hydronic Supply 8
368122 | F.F.L | Hydronic Supply 8
368127 | F.F.L | Hydronic Supply 8
368151 | T.O.F | Hydronic Supply 8
385773 | F.F.L | Sanitary 6
405806 | F.F.L | Domestic Cold Water 1
405808 | F.F.L | Domestic Cold Water 1
405838 | F.F.L | Domestic Cold Water 1
408237 | F.F.L | Domestic Hot Water 1
408241 | F.F.L | Domestic Hot Water 1
408244 | F.F.L | Domestic Hot Water 1
409378 | F.F.L | Domestic Hot Water 1
463074 | F.F.L | Domestic Cold Water 1
463080 | F.F.L | Domestic Cold Water 1
463083 | F.F.L | Domestic Cold Water 1
463121 | F.F.L | Domestic Hot Water 1
463127 | F.F.L | Domestic Hot Water 1
463130 | F.F.L | Domestic Hot Water 1
463758 | F.F.L | Domestic Hot Water 1
463762 | F.F.L | Domestic Hot Water 1
472611 | F.F.L | Domestic Cold Water 1
472615 | F.F.L | Domestic Cold Water 1
513116 | F.F.L | Domestic Cold Water 1
513120 | F.F.L | Domestic Cold Water 1
513127 | F.F.L | Domestic Cold Water 1
513627 | F.F.L | Domestic Hot Water 1
514019 | F.F.L | Domestic Hot Water 1
514023 | F.F.L | Domestic Hot Water 1
514052 | F.F.L | Domestic Hot Water 1
514055 | F.F.L | Domestic Hot Water 1
514591 | F.F.L | Domestic Hot Water 1
515041 | F.F.L | Sanitary 4
515243 | F.F.L | Sanitary 4
516499 | F.F.L | Sanitary 4
516502 | F.F.L | Sanitary 4
516522 | F.F.L | Sanitary 4
517329 | F.F.L | Hydronic Supply 8; Sanitary 4
517331 | F.F.L | Hydronic Supply 8
517338 | T.O.F | Hydronic Supply 8
517352 | T.O.F | Hydronic Supply 8
517539 | F.F.L | Domestic Cold Water 1
517548 | F.F.L | Domestic Cold Water 1
517564 | F.F.L | Domestic Cold Water 1
517577 | F.F.L | Domestic Cold Water 1
526766 | F.F.L | Domestic Hot Water 1
526978 | F.F.L | Domestic Hot Water 1
527025 | F.F.L | Domestic Hot Water 1
527109 | F.F.L | Domestic Hot Water 1
527168 | F.F.L | Domestic Hot Water 1
527207 | F.F.L | Domestic Cold Water 1
527248 | F.F.L | Domestic Cold Water 1
527281 | F.F.L | Domestic Cold Water 1
527371 | F.F.L | Domestic Hot Water 1
527373 | F.F.L | Domestic Hot Water 1
761439 | F.F.L | Domestic Hot Water 1
761441 | F.F.L | Domestic Hot Water 1
761551 | F.F.L | Domestic Hot Water 1
763469 | F.F.L | Domestic Cold Water 1
763900 | F.F.L | Hydronic Supply 8
764034 | F.F.L | Hydronic Supply 8
764122 | F.F.L | Hydronic Supply 8
764550 | F.F.L
764737 | F.F.L | Hydronic Supply 8
764747 | T.O.F | Hydronic Supply 8
769086 | F.F.L | Hydronic Supply 8; Sanitary 6
769089 | F.F.L | Hydronic Supply 8
769102 | F.F.L | Hydronic Supply 8
1316409 | F.F.L | Hydronic Supply 8
1316411 | F.F.L | Hydronic Supply 8
1316433 | T.O.F | Hydronic Supply 8

# IfcFlowTerminal: 1065 mmx535 mm - Public, M_Sink - Kitchen - Double:1065 mmx535 mm - Public:511864
In: 2
Pset_DistributionFlowElementCommon - Reference: 1065 mmx535 mm - Public
Group: Domestic Cold Water 1; Domestic Hot Water 1; Sanitary 4

# IfcFlowTerminal: 1525 mmx760 mm - Public, M_Bath Tub:1525 mmx760 mm - Public:356694
In: 3
Pset_DistributionFlowElementCommon - Reference: 1525 mmx760 mm - Public
Group: Domestic Cold Water 1; Hydronic Supply 2; Domestic Hot Water 1

# IfcFlowTerminal: 212507000 White, Shower tray, sanitary acrylic 1400x800x45-Solutions-Laufen-212507:212507000 White:429385
In: F.F.L
Pset_DistributionFlowElementCommon - Reference: 212507000 White

# IfcFlowTerminal: 485 mmx355 mm - Private (2)
Pset_DistributionFlowElementCommon - Reference: 485 mmx355 mm - Private
Name (M_Lavatory - Wall Mounted:485 mmx355 mm - Private:...) | In | Group
366079 | 3 | Domestic Cold Water 1; Domestic Hot Water 1
366115 | 4 | Domestic Cold Water 1; Domestic Hot Water 1; Sanitary 6

# IfcFlowTerminal: LED15FM12-W120 (5)
In: T.O.F
Type - Material: Glass, White, High Luminance, Steel, Paint Finish, Ivory, Glossy
Pset_ElectricalDeviceCommon - NumberOfPoles: 1
Pset_DistributionFlowElementCommon - Reference: LED15FM12-W120
Name (M_Downlight - Round - LED:LED15FM12-W120:...)
1965649
1966520
1966646
1966732
1966834

# IfcFlowTerminal: Plumbing_Fixture-Grohe-Sena-Hand_shower_1_spray-12-METRIC, Plumbing_Fixture-Grohe-Sena-Hand_shower_1_spray-12-METRIC:Plumbing_Fixture-Grohe-Sena-Hand_shower_1_spray-12-METRIC:436320
In: F.F.L
Classification: C1030220 Bath & Toilet Accessories - Residential (Uniformat); Material: Grohe-Chrome
Pset_ManufacturerTypeInformation - Manufacturer: Grohe AG
Pset_DistributionFlowElementCommon - Reference: Plumbing_Fixture-Grohe-Sena-Hand_shower_1_spray-12-METRIC

# IfcFlowTerminal: Rainshower 27 032 001, Plumbing_Fixtures-Grohe-Rainshower-Shower_System_210-wall_mounted-12-METRIC:Rainshower 27 032 001:436318
In: 4
Classification: C1030220 Bath & Toilet Accessories - Residential (Uniformat); Material: Grohe-Chrome; Group: Domestic Cold Water 1; Domestic Hot Water 1
Pset_ManufacturerTypeInformation - Manufacturer: Grohe AG
Pset_DistributionFlowElementCommon - Reference: Rainshower 27 032 001

# IfcFlowTerminal: Retention tray, M_Sink - Work:Retention tray:391891
In: F.F.L
Pset_DistributionFlowElementCommon - Reference: Retention tray
Group: Hydronic Supply 6

# IfcFlowTerminal: Sanitary_Shower-screens_Gala_Klevan_F-front-enclosure_1400mm, Sanitary_Shower-screens_Gala_Klevan_F-front-enclosure_1400mm:Sanitary_Shower-screens_Gala_Klevan_F-front-enclosure_1400mm:431555
In: 4
Material: 7bae24e2_9eaf_436f_80aa_9e7020457650, dbcda8c5_9ad4_4e30_a574_38c062b7739d
Pset_DistributionFlowElementCommon - Reference: Sanitary_Shower-screens_Gala_Klevan_F-front-enclosure_1400mm

# IfcFooting: Wall Foundation:Footing - 200 X 150 (2)
In: T.O.F
PredefinedType: STRIP_FOOTING; Material: Concrete 10Mpa
Pset_ManufacturerTypeInformation - Manufacturer: Lafarge
Name (Wall Foundation:Footing - 200 X 150:...)
591624
591626

# IfcFooting: Wall Foundation:R.C Footing - 450 X 230 (17)
In: T.O.F
PredefinedType: STRIP_FOOTING; Material: Concrete 10Mpa
Pset_ManufacturerTypeInformation - Manufacturer: Lafarge
Name (Wall Foundation:R.C Footing - 450 X 230:...)
252561
252572
252584
252595
252606
252637
252648
257568
568256
570805
570842
570867
571514
577258
577269
591137
1304410

# IfcFooting: Wall Foundation:R.C Footing - 600 X 230 (13)
In: T.O.F
PredefinedType: STRIP_FOOTING; Material: Concrete 10Mpa
Pset_ManufacturerTypeInformation - Manufacturer: Lafarge
Name (Wall Foundation:R.C Footing - 600 X 230:...)
251758
251767
251777
251787
251797
251806
251815
251824
251834
251853
252385
253132
571778

# IfcFurnishingElement: 1000mm (2)
In: 2
Type - ElementType: 1000mm; Material: Cabinets, Cabinets - Handles
Name (M_Base Cabinet-Double Door & 2 Drawer:1000mm:...)
774363
774458

# IfcFurnishingElement: 1200mm, M_Base Cabinet-Double Door Sink Unit:1200mm:772821
In: 2
Type - ElementType: 1200mm; Material: Cabinets, Cabinets - Handles

# IfcFurnishingElement: 1372 x 1905mm - Double (2)
Type - ElementType: 1372 x 1905mm - Double; Material: Textile - White, Metal - Chrome
Name (M_Bed-Standard:1372 x 1905mm - Double:...) | In
752090 | 7
752654 | 5

# IfcFurnishingElement: 1981 x 2032mm - King, M_Bed-Standard:1981 x 2032mm - King:754524
In: 9
Type - ElementType: 1981 x 2032mm - King; Material: Textile - White, Metal - Chrome

# IfcFurnishingElement: 3 Posti (230 x 92 cm), Sofa_-_3_Seat:3 Posti (230 x 92 cm):760087
In: 6
Type - ElementType: 3 Posti (230 x 92 cm)
Pset_ManufacturerTypeInformation - Manufacturer: Revit

# IfcFurnishingElement: 600mm Depth, M_Counter Top w Sink Hole:600mm Depth:774980
In: 2
Type - ElementType: 600mm Depth; Material: Concrete, Lightweight

# IfcFurnishingElement: Coffee_Table_854, Coffee_Table_854:Coffee_Table_854:760940
In: 6
Type - ElementType: Coffee_Table_854

# IfcFurnishingElement: IKEA_Smadal_Glass_Cabinet, IKEA_Smadal_Glass_Cabinet:IKEA_Smadal_Glass_Cabinet:758771
In: 6
Type - ElementType: IKEA_Smadal_Glass_Cabinet; Material: Glass, Brushed Aluminium, Oak

# IfcFurnishingElement: plasma_screen_with_full_home_theatre_system, plasma_screen_with_full_home_theatre_system:plasma_screen_with_full_home_theatre_system:757438
In: 6
Type - ElementType: plasma_screen_with_full_home_theatre_system; Material: cd cover, tv frame, tv screen, steel frame, Default 2, Glass

# IfcOpeningElement: Opening (26)
Name | In
Basic Wall:BrickWall - 110mm (Ext.F&Int.F):199384 | F.F.L | Pset_ManufacturerTypeInformation - Manufacturer: Kurland - Face brick
2 x Basic Wall:BrickWall - 110mm (Ext.F&Int.F):205191 | F.F.L | Pset_ManufacturerTypeInformation - Manufacturer: Kurland - Face brick
Basic Wall:BrickWall - 270mm (Ext.F&Int.S):199869 | F.F.L | Pset_ManufacturerTypeInformation - Manufacturer: Durango - Stock bricks and Kurland - Face bricks
2 x Basic Wall:BrickWall - 270mm (Ext.F&Int.F):245736 | F.F.L | Pset_ManufacturerTypeInformation - Manufacturer: Kurland - Face brick
Tpl All Bars1:Tpl All Bars 3:1304400:1 | F.F.L
Tpl All Bars1:Tpl All Bars 3:1304393:1 | F.F.L
Tpl All Bars1:Tpl All Bars 2:1304389:1 | F.F.L
M_Single-Flush:0813 x 2134mm:842625:1 | F.F.L
Tpl All Bars1:Tpl All Bars 4:558829:1 | F.F.L
Sgl All Bars:M_Casement 2x3:298176:1 | F.F.L
Tpl All Bars1:Tpl All Bars 5:296256:1 | F.F.L
M_Counter Top w Sink Hole:600mm Depth:774980:1 | 2
M_Single-Flush:0813 x 2134mm:282405:1 | F.F.L
M_Single-Flush:0915 x 2134mm:283297:1 | F.F.L
Tpl All Bars1:Tpl All Bars 4:296380:1 | F.F.L
Sgl All Bars:M_Casement 2x3:304321:1 | F.F.L
Tpl All Bars1:Tpl All Bars:1304704:1 | F.F.L
M_Door-Interior-Double-Full Glass-Wood:1800 x 2100mm:291945:1 | F.F.L
Sgl All Bars:M_Casement 2x3:304057:1 | F.F.L
Sgl All Bars:M_Casement 2x3:303982:1 | F.F.L
M_Overhead-Sectional:2435 x 1981mm:306219:1 | F.F.L
M_Single-Flush:0915 x 2134mm:283172:1 | F.F.L
M_Single-Glass 2:0813 x 2134mm:373462:1 | F.F.L
M_Single-Flush:0813 x 2134mm:282503:1 | F.F.L

# IfcRailing: Railing:900mm Pipe (3)
Pset_RailingCommon - IsExternal: no; Reference: 900mm Pipe; Height: 900 mm
Name (Railing:900mm Pipe:...) | In
843244 | T.O.F
843248 | T.O.F
843649 | F.F.L

# IfcRamp: Ramp:Ramp 1:15922, Ramp:Ramp 1:842788
In: T.O.F
Pset_RampCommon - IsExternal: no; Reference: Ramp 1

# IfcRamp: Ramp:Ramp 2:843379, Ramp:Ramp 2:843122
In: T.O.F
Pset_RampCommon - IsExternal: no; Reference: Ramp 2

# IfcRampFlight: Ramp:Ramp 1:15922, Ramp:Ramp 1:842788:1
In: T.O.F
Material: Concrete, Cast In Situ
Pset_RampFlightCommon - Reference: Ramp 1

# IfcRampFlight: Ramp:Ramp 2:843379, Ramp:Ramp 2:843122:1
In: T.O.F
Material: Concrete, Cast In Situ
Pset_RampFlightCommon - Reference: Ramp 2

# IfcRoof: Basic Roof:roof 22mm foil (4)
In: U.S.W.P
Pset_RoofCommon - IsExternal: yes; Reference: roof 22mm foil
Name (Basic Roof:roof 22mm foil:...) | TotalArea (m2) | ProjectedArea (m2)
730602 | 11.818 | 10.9575
730612 | 71.6571 | 66.4393
730626 | 40.3521 | 37.4138
730636 | 17.836 | 16.5372

# IfcSlab: Basic Roof:roof 22mm foil (4)
In: U.S.W.P
PredefinedType: ROOF; Material: Default Roof 22 mm
Pset_SlabCommon - IsExternal: yes; Reference: roof 22mm foil; PitchAngle: 22 deg
Name (Basic Roof:roof 22mm foil:...)
730602
730612
730626
730636

# IfcSlab: Floor:Carpet (4)
PredefinedType: FLOOR; Material: Carpet 4 mm
Pset_SlabCommon - LoadBearing: no; IsExternal: no; PitchAngle: 0 deg; Reference: Carpet; ThermalTransmittance: 15 kg/K/s3
Pset_ManufacturerTypeInformation - Manufacturer: Lafarge
Name (Floor:Carpet:...) | In
1313142 | F.F.L
1313394 | F.F.L
1313528 | N.G.L
1314118 | F.F.L

# IfcSlab: Floor:Insitu Concrete 34mm, Floor:Insitu Concrete 34mm:1953194
In: F.F.L
PredefinedType: FLOOR; Material: Concrete, Lightweight 34 mm
Pset_SlabCommon - LoadBearing: no; IsExternal: no; PitchAngle: 0 deg; Reference: Insitu Concrete 34mm; ThermalTransmittance: 6.14706 kg/K/s3

# IfcSlab: Floor:Surfacebed 150mm (Screed,Concrete,Sandbed) (8)
In: F.F.L
PredefinedType: FLOOR; Material: Screed 30 mm, Concrete, Cast-in-Place gray 70 mm, Sandbed 50 mm
Pset_SlabCommon - LoadBearing: no; Reference: Surfacebed 150mm (Screed,Concrete,Sandbed); IsExternal: no; ThermalTransmittance: 4.62587 kg/K/s3; PitchAngle: 0 deg
Pset_ManufacturerTypeInformation - Manufacturer: Lafarge
Name (Floor:Surfacebed 150mm (Screed,Concrete,Sandbed):...)
269806
269833
272029
273079
336347
336434
375407
555780

# IfcSlab: Floor:Tiles (3)
In: F.F.L
PredefinedType: FLOOR; Material: Floor Tile 4 mm
Pset_SlabCommon - LoadBearing: no; IsExternal: no; PitchAngle: 0 deg; Reference: Tiles
Pset_ManufacturerTypeInformation - Manufacturer: Lafarge
Name (Floor:Tiles:...)
1311053
1314172
1314293

# IfcSlab: Floor:Tiles - Teracota 2, Floor:Tiles - Teracota 2:1312154
In: F.F.L
PredefinedType: FLOOR; Material: Tile - Teracota 4 mm
Pset_SlabCommon - LoadBearing: no; IsExternal: no; PitchAngle: 0 deg; Reference: Tiles - Teracota 2
Pset_ManufacturerTypeInformation - Manufacturer: Lafarge

# IfcWallStandardCase: Basic Wall:110mm BrickWall (Int.Pl&Ext.Pl), Basic Wall:110mm BrickWall (Int.Pl&Ext.Pl):342329
In: F.F.L
Type - PredefinedType: STANDARD; Material: Plaster 10 mm, Brick, Common 110 mm, Plaster 10 mm
Pset_WallCommon - LoadBearing: no; IsExternal: yes; ExtendToStructure: no; Reference: 110mm BrickWall (Int.Pl&Ext.Pl); ThermalTransmittance: 4.90909 kg/K/s3

# IfcWallStandardCase: Basic Wall:BrickWall - 110mm (2)
In: T.O.F
Type - PredefinedType: STANDARD; Material: Brickwork - 110mm (Stock) 110 mm
Pset_WallCommon - LoadBearing: no; IsExternal: yes; ExtendToStructure: no; Reference: BrickWall - 110mm
Pset_ManufacturerTypeInformation - Manufacturer: Kurland - Face brick
Name (Basic Wall:BrickWall - 110mm:...)
591621
591622

# IfcWallStandardCase: Basic Wall:BrickWall - 110mm (Ext.F&Int.F) (95)
Type - PredefinedType: STANDARD; Material: Brickwork - Facebrick (Plettenberg Autumn) 110 mm
Pset_WallCommon - LoadBearing: no; IsExternal: yes; Reference: BrickWall - 110mm (Ext.F&Int.F); ExtendToStructure: no
Pset_ManufacturerTypeInformation - Manufacturer: Kurland - Face brick
Name (Basic Wall:BrickWall - 110mm (Ext.F&Int.F):...) | In
199384 | F.F.L
199431 | F.F.L
200168 | F.F.L
203461 | F.F.L
203783 | F.F.L
204897 | F.F.L
204959 | F.F.L
204992 | F.F.L
205085 | F.F.L
220513 | F.F.L
342755 | F.F.L
533829 | N.G.L
535561 | N.G.L
535660 | N.G.L
535704 | N.G.L
536209 | N.G.L | Group: Model Group:Array Group 4:536213
536210 | N.G.L | Group: Model Group:Array Group 4:536213
536211 | N.G.L | Group: Model Group:Array Group 4:536213
536363 | N.G.L
543843 | N.G.L
543887 | N.G.L
544091 | N.G.L
544141 | N.G.L
544215 | N.G.L
544260 | N.G.L
544416 | N.G.L
544457 | N.G.L
544560 | N.G.L
544621 | N.G.L
545124 | N.G.L
545207 | N.G.L
545256 | N.G.L
545346 | N.G.L
545395 | N.G.L
545563 | N.G.L
545609 | N.G.L
545673 | N.G.L
545727 | N.G.L
545791 | N.G.L
545843 | N.G.L
547837 | N.G.L
547907 | N.G.L
547989 | N.G.L
548104 | N.G.L
549517 | N.G.L
549569 | N.G.L
549625 | N.G.L
549696 | N.G.L
550967 | N.G.L
551152 | N.G.L
551225 | N.G.L
551432 | N.G.L
551481 | N.G.L
551539 | N.G.L
551593 | N.G.L
551744 | N.G.L
551800 | N.G.L
553032 | N.G.L
553191 | N.G.L
553249 | N.G.L
553306 | N.G.L
553358 | N.G.L
553461 | N.G.L
553577 | N.G.L
553622 | N.G.L
553672 | N.G.L
554444 | N.G.L
554624 | N.G.L
554834 | N.G.L
570080 | N.G.L
570128 | N.G.L
570396 | N.G.L
570462 | N.G.L
570523 | N.G.L
570598 | N.G.L
570654 | N.G.L
572802 | N.G.L
572886 | N.G.L
572918 | N.G.L
573087 | N.G.L
573125 | N.G.L
573166 | N.G.L
573201 | N.G.L
573591 | N.G.L
573939 | N.G.L
573967 | N.G.L
574022 | N.G.L
574136 | N.G.L
574535 | N.G.L
574637 | N.G.L
574663 | N.G.L
576977 | N.G.L
591617 | N.G.L
591618 | N.G.L
1304538 | N.G.L

# IfcWallStandardCase: Basic Wall:BrickWall - 220mm (Ext.F&Int.F) 2 (2)
In: N.G.L
Type - PredefinedType: STANDARD; Material: Brickwork - Facebrick (Plettenberg Autumn) 220 mm
Pset_WallCommon - LoadBearing: no; IsExternal: yes; ExtendToStructure: no; Reference: BrickWall - 220mm (Ext.F&Int.F) 2
Pset_ManufacturerTypeInformation - Manufacturer: Kurland - Face brick
Name (Basic Wall:BrickWall - 220mm (Ext.F&Int.F) 2:...)
536124
536212 | Group: Model Group:Array Group 4:536213

# IfcWallStandardCase: Basic Wall:BrickWall - 230mm (Ext.F&Int.S) (3)
In: U.S.W.P
Type - PredefinedType: STANDARD; Material: Brickwork - Facebrick (Plettenberg Autumn) 110 mm, Plaster 10 mm, Brickwork - 110mm (Stock) 110 mm
Pset_WallCommon - LoadBearing: no; ExtendToStructure: yes; IsExternal: yes; Reference: BrickWall - 230mm (Ext.F&Int.S)
Pset_ManufacturerTypeInformation - Manufacturer: Stock bricks
Name (Basic Wall:BrickWall - 230mm (Ext.F&Int.S):...)
1308043
1308287
1308526

# IfcWallStandardCase: Basic Wall:BrickWall - 230mm (Ext.F&Int.S) 2 (2)
In: U.S.W.P
Type - PredefinedType: STANDARD; Material: Brickwork - 110mm (Stock) 110 mm, Plaster 10 mm, Brickwork - Facebrick (Plettenberg Autumn) 110 mm
Pset_WallCommon - LoadBearing: no; ExtendToStructure: yes; IsExternal: yes; Reference: BrickWall - 230mm (Ext.F&Int.S) 2
Pset_ManufacturerTypeInformation - Manufacturer: Stock bricks
Name (Basic Wall:BrickWall - 230mm (Ext.F&Int.S) 2:...)
1314681
1315130

# IfcWallStandardCase: Basic Wall:BrickWall - 230mm (Ext.S&Int.S) (6)
Type - PredefinedType: STANDARD; Material: Brickwork - 110mm (Stock) 110 mm, Plaster 10 mm, Brickwork - 110mm (Stock) 110 mm
Pset_WallCommon - LoadBearing: no; IsExternal: yes; Reference: BrickWall - 230mm (Ext.S&Int.S)
Pset_ManufacturerTypeInformation - Manufacturer: Stock bricks
Name (Basic Wall:BrickWall - 230mm (Ext.S&Int.S):...) | In | ExtendToStructure
201466 | F.F.L | no
201590 | F.F.L | no
202871 | F.F.L | no
1309439 | U.S.W.P | yes
1315864 | U.S.W.P | yes
1315943 | U.S.W.P | yes

# IfcWallStandardCase: Basic Wall:BrickWall - 270mm (Ext.F&Int.F) (3)
In: F.F.L
Type - PredefinedType: STANDARD; Material: Brickwork - Facebrick (Plettenberg Autumn) 110 mm, Air Infiltration Barrier 50 mm, Brickwork - Facebrick (Plettenberg Autumn) 110 mm
Pset_WallCommon - LoadBearing: no; IsExternal: yes; Reference: BrickWall - 270mm (Ext.F&Int.F); ThermalTransmittance: 1.2 kg/K/s3
Pset_ManufacturerTypeInformation - Manufacturer: Kurland - Face brick
Name (Basic Wall:BrickWall - 270mm (Ext.F&Int.F):...) | ExtendToStructure
200794 | yes
202428 | yes
202576 | no

# IfcWallStandardCase: Basic Wall:BrickWall - 270mm (Ext.F&Int.S) (4)
In: F.F.L
Type - PredefinedType: STANDARD; Material: Brickwork - Facebrick (Plettenberg Autumn) 110 mm, Air Infiltration Barrier 50 mm, Brickwork - 110mm (Stock) 110 mm, Plaster 10 mm
Pset_WallCommon - Reference: BrickWall - 270mm (Ext.F&Int.S); LoadBearing: no; ExtendToStructure: yes; IsExternal: yes; ThermalTransmittance: 1.2 kg/K/s3
Pset_ManufacturerTypeInformation - Manufacturer: Durango - Stock bricks and Kurland - Face bricks
Name (Basic Wall:BrickWall - 270mm (Ext.F&Int.S):...)
199059
199869
246016
410055

# IfcWallStandardCase: Basic Wall:BrickWall - 270mm (Ext.F&Int.S) 2 (3)
In: F.F.L
Type - PredefinedType: STANDARD; Material: Plaster 10 mm, Brickwork - 110mm (Stock) 110 mm, Air Infiltration Barrier 50 mm, Brickwork - Facebrick (Plettenberg Autumn) 110 mm
Pset_WallCommon - LoadBearing: no; IsExternal: yes; Reference: BrickWall - 270mm (Ext.F&Int.S) 2; ThermalTransmittance: 1.2 kg/K/s3
Pset_ManufacturerTypeInformation - Manufacturer: Durango - Stock bricks and Kurland - Face bricks
Name (Basic Wall:BrickWall - 270mm (Ext.F&Int.S) 2:...) | ExtendToStructure
199926 | yes
200861 | no
203143 | no

# IfcWallStandardCase: Basic Wall:BrickWall Foundation- 230mm, Basic Wall:BrickWall Foundation- 230mm:575637
In: T.O.F
Type - PredefinedType: STANDARD; Material: Brickwork - 110mm (Stock) 110 mm, Air Infiltration Barrier 10 mm, Brickwork - 110mm (Stock) 110 mm
Pset_WallCommon - LoadBearing: no; IsExternal: yes; ExtendToStructure: no; Reference: BrickWall Foundation- 230mm; ThermalTransmittance: 6 kg/K/s3
Pset_ManufacturerTypeInformation - Manufacturer: Stock bricks

# IfcWallStandardCase: Basic Wall:BrickWall Foundation- 270mm 2, Basic Wall:BrickWall Foundation- 270mm 2:562695
In: T.O.F
Type - PredefinedType: STANDARD; Material: Brickwork - 110mm (Stock) 110 mm, Air Infiltration Barrier 50 mm, Brickwork - 110mm (Stock) 110 mm
Pset_WallCommon - LoadBearing: no; IsExternal: yes; ExtendToStructure: no; Reference: BrickWall Foundation- 270mm 2; ThermalTransmittance: 1.2 kg/K/s3
Pset_ManufacturerTypeInformation - Manufacturer: Stock bricks

# IfcWallStandardCase: Basic Wall:BrickWall Foundation- 340mm (21)
In: T.O.F
Type - PredefinedType: STANDARD; Material: Brickwork - 110mm (Stock) 110 mm, Air Infiltration Barrier 120 mm, Brickwork - 110mm (Stock) 110 mm
Pset_WallCommon - IsExternal: yes; ExtendToStructure: no; ThermalTransmittance: 0.5 kg/K/s3; Reference: BrickWall Foundation- 340mm
Pset_ManufacturerTypeInformation - Manufacturer: Stock bricks
Name (Basic Wall:BrickWall Foundation- 340mm:...) | LoadBearing
244142 | yes
246673 | yes
246945 | yes
247197 | yes
247466 | yes
248360 | yes
248885 | yes
249037 | yes
251333 | yes
252144 | yes
252988 | yes
257385 | yes
562450 | no
562515 | no
562859 | no
562966 | no
563005 | no
567338 | no
569611 | no
591136 | no
1304404 | no

# IfcWallStandardCase: Basic Wall:BrickWall Foundation- 340mm (2coarses F.) (8)
In: T.O.F
Type - PredefinedType: STANDARD; Material: Brickwork - 110mm (Stock) 110 mm, Air Infiltration Barrier 120 mm, Brickwork - Facebrick (Plettenberg Autumn) 110 mm
Pset_WallCommon - IsExternal: yes; ExtendToStructure: no; Reference: BrickWall Foundation- 340mm (2coarses F.); LoadBearing: yes; ThermalTransmittance: 0.5 kg/K/s3
Pset_ManufacturerTypeInformation - Manufacturer: Durango - Stock bricks and Kurland - Face bricks
Name (Basic Wall:BrickWall Foundation- 340mm (2coarses F.):...)
215015
215163
215257
215383
215473
215562
215713
215948

# IfcWallStandardCase: Basic Wall:Foundation BrickWall - 110mm (3)
In: T.O.F
Type - PredefinedType: STANDARD; Material: Brickwork - 110mm (Stock) 110 mm
Pset_WallCommon - LoadBearing: no; IsExternal: yes; ExtendToStructure: no; Reference: Foundation BrickWall - 110mm
Pset_ManufacturerTypeInformation - Manufacturer: Kurland - Face brick
Name (Basic Wall:Foundation BrickWall - 110mm:...)
575797
576390
576689

# IfcWindow: M_Casement 2x3 (4)
In: F.F.L
Type - OperationType: SINGLE_PANEL; ParameterTakesPrecedence: no; Sizeable: no; Material: Meranti - Varnish Mat, Glass
OverallHeight: 1800 mm; OverallWidth: 600 mm; Classification: C1010710 Interior Glazed Openings (Uniformat)
Pset_WindowCommon - IsExternal: yes; Reference: M_Casement 2x3; ThermalTransmittance: 3.6886 kg/K/s3
Pset_ManufacturerTypeInformation - Manufacturer: Swartland
Name (Sgl All Bars:M_Casement 2x3:...)
298176
303982
304057
304321

# IfcWindow: Tpl All Bars, Tpl All Bars1:Tpl All Bars:1304704
In: F.F.L
Type - OperationType: TRIPLE_PANEL_VERTICAL; ParameterTakesPrecedence: no; Sizeable: no; Material: Meranti - Varnish Mat, Glass
OverallHeight: 900 mm; OverallWidth: 2200 mm; Classification: C1010710 Interior Glazed Openings (Uniformat)
Pset_WindowCommon - IsExternal: yes; Reference: Tpl All Bars; ThermalTransmittance: 3.6886 kg/K/s3
Pset_ManufacturerTypeInformation - Manufacturer: Swartland

# IfcWindow: Tpl All Bars 2, Tpl All Bars1:Tpl All Bars 2:1304389
In: F.F.L
Type - OperationType: TRIPLE_PANEL_VERTICAL; ParameterTakesPrecedence: no; Sizeable: no; Material: Meranti - Varnish Mat, Glass
OverallHeight: 600 mm; OverallWidth: 2200 mm
Pset_WindowCommon - IsExternal: yes; Reference: Tpl All Bars 2
Pset_ManufacturerTypeInformation - Manufacturer: Swartland

# IfcWindow: Tpl All Bars 3 (2)
In: F.F.L
Type - OperationType: TRIPLE_PANEL_VERTICAL; ParameterTakesPrecedence: no; Sizeable: no; Material: Meranti - Varnish Mat, Glass
OverallHeight: 600 mm; OverallWidth: 900 mm
Pset_WindowCommon - IsExternal: yes; Reference: Tpl All Bars 3
Pset_ManufacturerTypeInformation - Manufacturer: Swartland
Name (Tpl All Bars1:Tpl All Bars 3:...)
1304393
1304400

# IfcWindow: Tpl All Bars 4 (2)
In: F.F.L
Type - OperationType: TRIPLE_PANEL_VERTICAL; ParameterTakesPrecedence: no; Sizeable: no; Material: Meranti - Varnish Mat, Glass
OverallHeight: 1600 mm; OverallWidth: 2200 mm
Pset_WindowCommon - IsExternal: yes; Reference: Tpl All Bars 4
Pset_ManufacturerTypeInformation - Manufacturer: Swartland
Name (Tpl All Bars1:Tpl All Bars 4:...)
296380
558829

# IfcWindow: Tpl All Bars 5, Tpl All Bars1:Tpl All Bars 5:296256
In: F.F.L
Type - OperationType: TRIPLE_PANEL_VERTICAL; ParameterTakesPrecedence: no; Sizeable: no; Material: Meranti - Varnish Mat, Glass
OverallHeight: 1600 mm; OverallWidth: 2200 mm
Pset_WindowCommon - IsExternal: yes; Reference: Tpl All Bars 5
Pset_ManufacturerTypeInformation - Manufacturer: Swartland
